One B-rep face of a CAD part: STEP entity #1350.
In plain terms, the planar face has unit normal (-0.707, 0, 0.707).
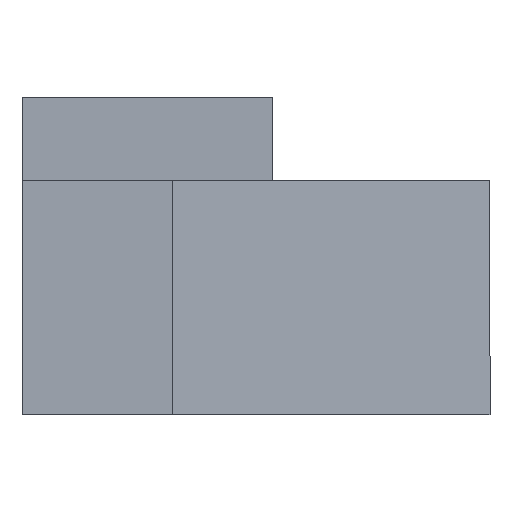
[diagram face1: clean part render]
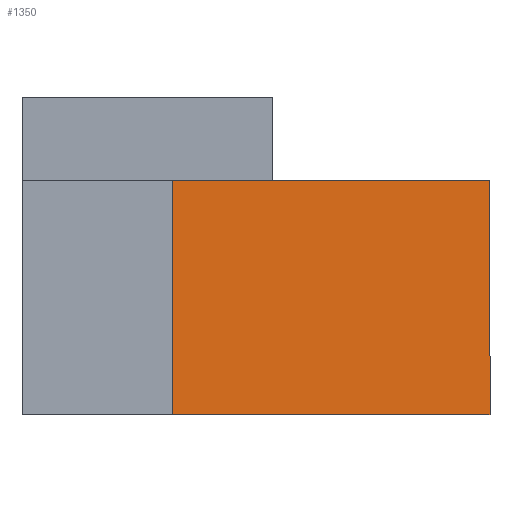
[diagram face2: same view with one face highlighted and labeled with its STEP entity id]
Its self-contained STEP definition (entity closure, numbers rounded to 3 decimals):
#62 = PLANE('',#63);
#63 = AXIS2_PLACEMENT_3D('',#64,#65,#66);
#64 = CARTESIAN_POINT('',(55.,173.2,1.96));
#65 = DIRECTION('',(-0.,-1.,-0.));
#66 = DIRECTION('',(0.,0.,-1.));
#90 = PLANE('',#91);
#91 = AXIS2_PLACEMENT_3D('',#92,#93,#94);
#92 = CARTESIAN_POINT('',(51.2,173.2,1.8));
#93 = DIRECTION('',(-1.,0.,0.));
#94 = DIRECTION('',(0.,0.,-1.));
#118 = PLANE('',#119);
#119 = AXIS2_PLACEMENT_3D('',#120,#121,#122);
#120 = CARTESIAN_POINT('',(55.,176.,1.5));
#121 = DIRECTION('',(-0.,-1.,-0.));
#122 = DIRECTION('',(0.,0.,-1.));
#214 = VERTEX_POINT('',#215);
#215 = CARTESIAN_POINT('',(51.2,173.2,1.8));
#965 = VERTEX_POINT('',#966);
#966 = CARTESIAN_POINT('',(55.,173.2,5.6));
#980 = PLANE('',#981);
#981 = AXIS2_PLACEMENT_3D('',#982,#983,#984);
#982 = CARTESIAN_POINT('',(58.8,173.2,1.8));
#983 = DIRECTION('',(0.707,-0.,0.707));
#984 = DIRECTION('',(-0.707,0.,0.707));
#992 = EDGE_CURVE('',#965,#214,#993,.T.);
#993 = SURFACE_CURVE('',#994,(#998,#1005),.PCURVE_S1.);
#994 = LINE('',#995,#996);
#995 = CARTESIAN_POINT('',(55.,173.2,5.6));
#996 = VECTOR('',#997,1.);
#997 = DIRECTION('',(-0.707,0.,-0.707));
#998 = PCURVE('',#62,#999);
#999 = DEFINITIONAL_REPRESENTATION('',(#1000),#1004);
#1000 = LINE('',#1001,#1002);
#1001 = CARTESIAN_POINT('',(-3.64,0.));
#1002 = VECTOR('',#1003,1.);
#1003 = DIRECTION('',(0.707,-0.707));
#1004 = ( GEOMETRIC_REPRESENTATION_CONTEXT(2) 
PARAMETRIC_REPRESENTATION_CONTEXT() REPRESENTATION_CONTEXT('2D SPACE',''
  ) );
#1005 = PCURVE('',#1006,#1011);
#1006 = PLANE('',#1007);
#1007 = AXIS2_PLACEMENT_3D('',#1008,#1009,#1010);
#1008 = CARTESIAN_POINT('',(55.,173.2,5.6));
#1009 = DIRECTION('',(-0.707,0.,0.707));
#1010 = DIRECTION('',(-0.707,0.,-0.707));
#1011 = DEFINITIONAL_REPRESENTATION('',(#1012),#1016);
#1012 = LINE('',#1013,#1014);
#1013 = CARTESIAN_POINT('',(0.,0.));
#1014 = VECTOR('',#1015,1.);
#1015 = DIRECTION('',(1.,0.));
#1016 = ( GEOMETRIC_REPRESENTATION_CONTEXT(2) 
PARAMETRIC_REPRESENTATION_CONTEXT() REPRESENTATION_CONTEXT('2D SPACE',''
  ) );
#1258 = VERTEX_POINT('',#1259);
#1259 = CARTESIAN_POINT('',(51.2,176.,1.8));
#1280 = EDGE_CURVE('',#1281,#1258,#1283,.T.);
#1281 = VERTEX_POINT('',#1282);
#1282 = CARTESIAN_POINT('',(52.4,176.,3.));
#1283 = SURFACE_CURVE('',#1284,(#1288,#1295),.PCURVE_S1.);
#1284 = LINE('',#1285,#1286);
#1285 = CARTESIAN_POINT('',(55.,176.,5.6));
#1286 = VECTOR('',#1287,1.);
#1287 = DIRECTION('',(-0.707,0.,-0.707));
#1288 = PCURVE('',#118,#1289);
#1289 = DEFINITIONAL_REPRESENTATION('',(#1290),#1294);
#1290 = LINE('',#1291,#1292);
#1291 = CARTESIAN_POINT('',(-4.1,0.));
#1292 = VECTOR('',#1293,1.);
#1293 = DIRECTION('',(0.707,-0.707));
#1294 = ( GEOMETRIC_REPRESENTATION_CONTEXT(2) 
PARAMETRIC_REPRESENTATION_CONTEXT() REPRESENTATION_CONTEXT('2D SPACE',''
  ) );
#1295 = PCURVE('',#1006,#1296);
#1296 = DEFINITIONAL_REPRESENTATION('',(#1297),#1301);
#1297 = LINE('',#1298,#1299);
#1298 = CARTESIAN_POINT('',(0.,-2.8));
#1299 = VECTOR('',#1300,1.);
#1300 = DIRECTION('',(1.,0.));
#1301 = ( GEOMETRIC_REPRESENTATION_CONTEXT(2) 
PARAMETRIC_REPRESENTATION_CONTEXT() REPRESENTATION_CONTEXT('2D SPACE',''
  ) );
#1327 = EDGE_CURVE('',#214,#1258,#1328,.T.);
#1328 = SURFACE_CURVE('',#1329,(#1333,#1340),.PCURVE_S1.);
#1329 = LINE('',#1330,#1331);
#1330 = CARTESIAN_POINT('',(51.2,173.2,1.8));
#1331 = VECTOR('',#1332,1.);
#1332 = DIRECTION('',(0.,1.,0.));
#1333 = PCURVE('',#90,#1334);
#1334 = DEFINITIONAL_REPRESENTATION('',(#1335),#1339);
#1335 = LINE('',#1336,#1337);
#1336 = CARTESIAN_POINT('',(0.,-0.));
#1337 = VECTOR('',#1338,1.);
#1338 = DIRECTION('',(0.,-1.));
#1339 = ( GEOMETRIC_REPRESENTATION_CONTEXT(2) 
PARAMETRIC_REPRESENTATION_CONTEXT() REPRESENTATION_CONTEXT('2D SPACE',''
  ) );
#1340 = PCURVE('',#1006,#1341);
#1341 = DEFINITIONAL_REPRESENTATION('',(#1342),#1346);
#1342 = LINE('',#1343,#1344);
#1343 = CARTESIAN_POINT('',(5.374,0.));
#1344 = VECTOR('',#1345,1.);
#1345 = DIRECTION('',(0.,-1.));
#1346 = ( GEOMETRIC_REPRESENTATION_CONTEXT(2) 
PARAMETRIC_REPRESENTATION_CONTEXT() REPRESENTATION_CONTEXT('2D SPACE',''
  ) );
#1350 = ADVANCED_FACE('',(#1351),#1006,.T.);
#1351 = FACE_BOUND('',#1352,.T.);
#1352 = EDGE_LOOP('',(#1353,#1376,#1402,#1403,#1404));
#1353 = ORIENTED_EDGE('',*,*,#1354,.T.);
#1354 = EDGE_CURVE('',#965,#1355,#1357,.T.);
#1355 = VERTEX_POINT('',#1356);
#1356 = CARTESIAN_POINT('',(55.,176.,5.6));
#1357 = SURFACE_CURVE('',#1358,(#1362,#1369),.PCURVE_S1.);
#1358 = LINE('',#1359,#1360);
#1359 = CARTESIAN_POINT('',(55.,173.2,5.6));
#1360 = VECTOR('',#1361,1.);
#1361 = DIRECTION('',(0.,1.,0.));
#1362 = PCURVE('',#1006,#1363);
#1363 = DEFINITIONAL_REPRESENTATION('',(#1364),#1368);
#1364 = LINE('',#1365,#1366);
#1365 = CARTESIAN_POINT('',(0.,0.));
#1366 = VECTOR('',#1367,1.);
#1367 = DIRECTION('',(0.,-1.));
#1368 = ( GEOMETRIC_REPRESENTATION_CONTEXT(2) 
PARAMETRIC_REPRESENTATION_CONTEXT() REPRESENTATION_CONTEXT('2D SPACE',''
  ) );
#1369 = PCURVE('',#980,#1370);
#1370 = DEFINITIONAL_REPRESENTATION('',(#1371),#1375);
#1371 = LINE('',#1372,#1373);
#1372 = CARTESIAN_POINT('',(5.374,0.));
#1373 = VECTOR('',#1374,1.);
#1374 = DIRECTION('',(0.,-1.));
#1375 = ( GEOMETRIC_REPRESENTATION_CONTEXT(2) 
PARAMETRIC_REPRESENTATION_CONTEXT() REPRESENTATION_CONTEXT('2D SPACE',''
  ) );
#1376 = ORIENTED_EDGE('',*,*,#1377,.T.);
#1377 = EDGE_CURVE('',#1355,#1281,#1378,.T.);
#1378 = SURFACE_CURVE('',#1379,(#1383,#1390),.PCURVE_S1.);
#1379 = LINE('',#1380,#1381);
#1380 = CARTESIAN_POINT('',(55.,176.,5.6));
#1381 = VECTOR('',#1382,1.);
#1382 = DIRECTION('',(-0.707,0.,-0.707));
#1383 = PCURVE('',#1006,#1384);
#1384 = DEFINITIONAL_REPRESENTATION('',(#1385),#1389);
#1385 = LINE('',#1386,#1387);
#1386 = CARTESIAN_POINT('',(0.,-2.8));
#1387 = VECTOR('',#1388,1.);
#1388 = DIRECTION('',(1.,0.));
#1389 = ( GEOMETRIC_REPRESENTATION_CONTEXT(2) 
PARAMETRIC_REPRESENTATION_CONTEXT() REPRESENTATION_CONTEXT('2D SPACE',''
  ) );
#1390 = PCURVE('',#1391,#1396);
#1391 = PLANE('',#1392);
#1392 = AXIS2_PLACEMENT_3D('',#1393,#1394,#1395);
#1393 = CARTESIAN_POINT('',(55.,176.,1.96));
#1394 = DIRECTION('',(-0.,-1.,-0.));
#1395 = DIRECTION('',(0.,0.,-1.));
#1396 = DEFINITIONAL_REPRESENTATION('',(#1397),#1401);
#1397 = LINE('',#1398,#1399);
#1398 = CARTESIAN_POINT('',(-3.64,0.));
#1399 = VECTOR('',#1400,1.);
#1400 = DIRECTION('',(0.707,-0.707));
#1401 = ( GEOMETRIC_REPRESENTATION_CONTEXT(2) 
PARAMETRIC_REPRESENTATION_CONTEXT() REPRESENTATION_CONTEXT('2D SPACE',''
  ) );
#1402 = ORIENTED_EDGE('',*,*,#1280,.T.);
#1403 = ORIENTED_EDGE('',*,*,#1327,.F.);
#1404 = ORIENTED_EDGE('',*,*,#992,.F.);
